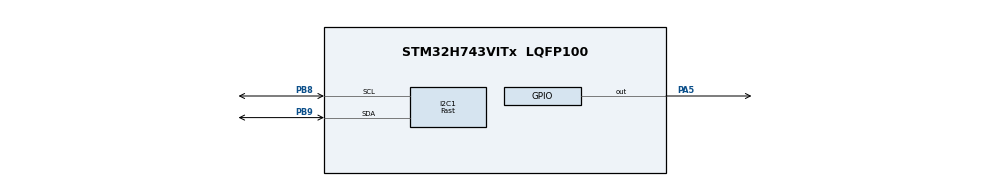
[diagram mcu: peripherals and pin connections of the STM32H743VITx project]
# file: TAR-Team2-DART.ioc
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CORTEX_M7.default_mode_Activation=1
I2C1.I2C_Speed_Mode=I2C_Fast
I2C1.Timing=0x00300F38
Mcu.Family=STM32H7
Mcu.Name=STM32H743VITx
Mcu.Package=LQFP100
NVIC.PriorityGroup=NVIC_PRIORITYGROUP_4
PA5.Signal=GPIO_Output
PB8.Mode=I2C
PB8.Signal=I2C1_SCL
PB9.Mode=I2C
PB9.Signal=I2C1_SDA
ProjectManager.HeapSize=0x200
ProjectManager.StackSize=0x400
ProjectManager.TargetToolchain=STM32CubeIDE
RCC.ADCFreq_Value=129000000
RCC.APB1Freq_Value=32000000
RCC.APB2Freq_Value=64000000
RCC.APB3Freq_Value=64000000
RCC.APB4Freq_Value=64000000
RCC.CortexFreq_Value=64000000
RCC.D2PPRE1=RCC_APB1_DIV2
RCC.HCLKFreq_Value=64000000
RCC.SYSCLKFreq_VALUE=64000000
RCC.USBFreq_Value=129000000
VP_MEMORYMAP_VS_MEMORYMAP.Mode=CurAppReg
board=custom

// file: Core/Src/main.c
/* USER CODE BEGIN Header */
/**
  ******************************************************************************
  * @file           : main.c
  * @brief          : Main program body
  ******************************************************************************
  * @attention
  *
  * Copyright (c) 2024 STMicroelectronics.
  * All rights reserved.
  *
  * This software is licensed under terms that can be found in the LICENSE file
  * in the root directory of this software component.
  * If no LICENSE file comes with this software, it is provided AS-IS.
  *
  ******************************************************************************
  */
/* USER CODE END Header */
#include "main.h"

void SystemClock_Config(void);
static void MPU_Config(void);
static void MX_GPIO_Init(void);

// Define I2C handler
I2C_HandleTypeDef hi2c1;

//global variables
#define MPU6050_ADDR 0x68

typedef struct {
    int16_t Accel_X;
    int16_t Accel_Y;
    int16_t Accel_Z;
    int16_t Gyro_X;
    int16_t Gyro_Y;
    int16_t Gyro_Z;
} MPU6050_Data;

void MX_I2C1_Init(void) {
  	//MPU6050 initialization
	hi2c1.Instance = I2C1;
	hi2c1.Init.OwnAddress1 = 0;
	hi2c1.Init.AddressingMode = I2C_ADDRESSINGMODE_7BIT;
	hi2c1.Init.DualAddressMode = I2C_DUALADDRESS_DISABLE;
	hi2c1.Init.OwnAddress2 = 0;
	hi2c1.Init.GeneralCallMode = I2C_GENERALCALL_DISABLE;
	hi2c1.Init.NoStretchMode = I2C_NOSTRETCH_DISABLE;
	if (HAL_I2C_Init(&hi2c1) != HAL_OK)
	{
		Error_Handler();
	}
}

// Function to write to MPU6050 register
void MPU6050_Write(uint8_t reg, uint8_t data)
{
    HAL_I2C_Mem_Write(&hi2c1, MPU6050_ADDR, reg, 1, &data, 1, HAL_MAX_DELAY);
}

// Function to read from MPU6050 register
void MPU6050_Read(uint8_t reg, uint8_t *buffer, uint16_t size)
{
    HAL_I2C_Mem_Read(&hi2c1, MPU6050_ADDR, reg, 1, buffer, size, HAL_MAX_DELAY);
}

void MPU6050_Init(void)
{
    // Wake up the MPU6050
    MPU6050_Write(0x6B, 0x00);  // Write 0 to PWR_MGMT_1 to wake up the MPU6050
}

void MPU6050_Read_All(MPU6050_Data *data)
{
    uint8_t buffer[14];
    MPU6050_Read(0x3B, buffer, 14);  // Read 14 bytes starting from ACCEL_XOUT_H

    // Accelerometer values
    data->Accel_X = (int16_t)(buffer[0] << 8 | buffer[1]);
    data->Accel_Y = (int16_t)(buffer[2] << 8 | buffer[3]);
    data->Accel_Z = (int16_t)(buffer[4] << 8 | buffer[5]);

    // Gyroscope values
    data->Gyro_X = (int16_t)(buffer[8] << 8 | buffer[9]);
    data->Gyro_Y = (int16_t)(buffer[10] << 8 | buffer[11]);
    data->Gyro_Z = (int16_t)(buffer[12] << 8 | buffer[13]);
}

int main(void)
{
  MPU_Config();
  HAL_Init();
  SystemClock_Config();
  MX_GPIO_Init();

  MPU6050_Init();
  MPU6050_Data sensor_data;

  MX_I2C1_Init();	//initialize I2C1 connection

  while (1)
  {
	  //LED TEST: toggle pin PA5
	  //HAL_GPIO_TogglePin(GPIOA, GPIO_PIN_5);
	  //HAL_Delay(100);

	  // Read accelerometer and gyroscope data
	  MPU6050_Read_All(&sensor_data);

	  HAL_Delay(500);
  }
}

void SystemClock_Config(void)
{
  RCC_OscInitTypeDef RCC_OscInitStruct = {0};
  RCC_ClkInitTypeDef RCC_ClkInitStruct = {0};

  /** Supply configuration update enable
  */
  HAL_PWREx_ConfigSupply(PWR_LDO_SUPPLY);

  /** Configure the main internal regulator output voltage
  */
  __HAL_PWR_VOLTAGESCALING_CONFIG(PWR_REGULATOR_VOLTAGE_SCALE3);

  while(!__HAL_PWR_GET_FLAG(PWR_FLAG_VOSRDY)) {}

  /** Initializes the RCC Oscillators according to the specified parameters
  * in the RCC_OscInitTypeDef structure.
  */
  RCC_OscInitStruct.OscillatorType = RCC_OSCILLATORTYPE_HSI;
  RCC_OscInitStruct.HSIState = RCC_HSI_DIV1;
  RCC_OscInitStruct.HSICalibrationValue = RCC_HSICALIBRATION_DEFAULT;
  RCC_OscInitStruct.PLL.PLLState = RCC_PLL_NONE;
  if (HAL_RCC_OscConfig(&RCC_OscInitStruct) != HAL_OK)
  {
    Error_Handler();
  }

  /** Initializes the CPU, AHB and APB buses clocks
  */
  RCC_ClkInitStruct.ClockType = RCC_CLOCKTYPE_HCLK|RCC_CLOCKTYPE_SYSCLK
                              |RCC_CLOCKTYPE_PCLK1|RCC_CLOCKTYPE_PCLK2
                              |RCC_CLOCKTYPE_D3PCLK1|RCC_CLOCKTYPE_D1PCLK1;
  RCC_ClkInitStruct.SYSCLKSource = RCC_SYSCLKSOURCE_HSI;
  RCC_ClkInitStruct.SYSCLKDivider = RCC_SYSCLK_DIV1;
  RCC_ClkInitStruct.AHBCLKDivider = RCC_HCLK_DIV1;
  RCC_ClkInitStruct.APB3CLKDivider = RCC_APB3_DIV1;
  RCC_ClkInitStruct.APB1CLKDivider = RCC_APB1_DIV1;
  RCC_ClkInitStruct.APB2CLKDivider = RCC_APB2_DIV1;
  RCC_ClkInitStruct.APB4CLKDivider = RCC_APB4_DIV1;

  if (HAL_RCC_ClockConfig(&RCC_ClkInitStruct, FLASH_LATENCY_1) != HAL_OK)
  {
    Error_Handler();
  }
}

static void MX_GPIO_Init(void)
{
  GPIO_InitTypeDef GPIO_InitStruct = {0};

  /* GPIO Ports Clock Enable */
  __HAL_RCC_GPIOA_CLK_ENABLE();
  __HAL_RCC_GPIOB_CLK_ENABLE();

  /*Configure GPIO pin Output Level */
  HAL_GPIO_WritePin(GPIOA, GPIO_PIN_5, GPIO_PIN_RESET);

  /*Configure GPIO pin : PA5 */
  GPIO_InitStruct.Pin = GPIO_PIN_5;
  GPIO_InitStruct.Mode = GPIO_MODE_OUTPUT_PP;
  GPIO_InitStruct.Pull = GPIO_NOPULL;
  GPIO_InitStruct.Speed = GPIO_SPEED_FREQ_LOW;
  HAL_GPIO_Init(GPIOA, &GPIO_InitStruct);

  /*Configure GPIO pins : PB8 PB9 */
  GPIO_InitStruct.Pin = GPIO_PIN_8|GPIO_PIN_9;
  GPIO_InitStruct.Mode = GPIO_MODE_AF_OD;
  GPIO_InitStruct.Pull = GPIO_NOPULL;
  GPIO_InitStruct.Speed = GPIO_SPEED_FREQ_LOW;
  GPIO_InitStruct.Alternate = GPIO_AF4_I2C1;
  HAL_GPIO_Init(GPIOB, &GPIO_InitStruct);
}

 /* MPU Configuration */

void MPU_Config(void)
{
  MPU_Region_InitTypeDef MPU_InitStruct = {0};

  /* Disables the MPU */
  HAL_MPU_Disable();

  /** Initializes and configures the Region and the memory to be protected
  */
  MPU_InitStruct.Enable = MPU_REGION_ENABLE;
  MPU_InitStruct.Number = MPU_REGION_NUMBER0;
  MPU_InitStruct.BaseAddress = 0x0;
  MPU_InitStruct.Size = MPU_REGION_SIZE_4GB;
  MPU_InitStruct.SubRegionDisable = 0x87;
  MPU_InitStruct.TypeExtField = MPU_TEX_LEVEL0;
  MPU_InitStruct.AccessPermission = MPU_REGION_NO_ACCESS;
  MPU_InitStruct.DisableExec = MPU_INSTRUCTION_ACCESS_DISABLE;
  MPU_InitStruct.IsShareable = MPU_ACCESS_SHAREABLE;
  MPU_InitStruct.IsCacheable = MPU_ACCESS_NOT_CACHEABLE;
  MPU_InitStruct.IsBufferable = MPU_ACCESS_NOT_BUFFERABLE;

  HAL_MPU_ConfigRegion(&MPU_InitStruct);
  /* Enables the MPU */
  HAL_MPU_Enable(MPU_PRIVILEGED_DEFAULT);

}

void Error_Handler(void)
{
  __disable_irq();
  while (1)
  {
  }
}
